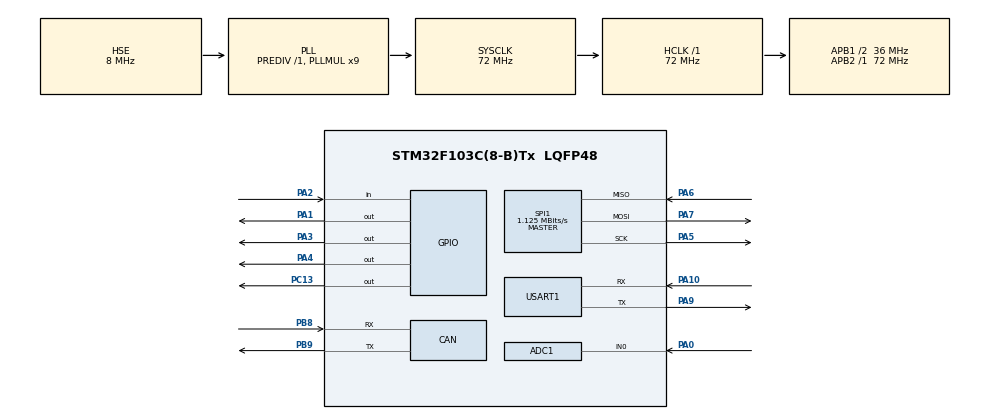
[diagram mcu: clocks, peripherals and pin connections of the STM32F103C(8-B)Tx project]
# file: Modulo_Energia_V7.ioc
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ADC1.Channel-0\#ChannelRegularConversion=ADC_CHANNEL_0
ADC1.ContinuousConvMode=ENABLE
ADC1.NbrOfConversion=1
ADC1.NbrOfConversionFlag=1
ADC1.Rank-0\#ChannelRegularConversion=1
ADC1.SamplingTime-0\#ChannelRegularConversion=ADC_SAMPLETIME_1CYCLE_5
ADC1.master=1
CAN.CalculateTimeBit=1333
CAN.CalculateTimeQuantum=444.44444444444446
Mcu.Family=STM32F1
Mcu.Name=STM32F103C(8-B)Tx
Mcu.Package=LQFP48
NVIC.PriorityGroup=NVIC_PRIORITYGROUP_4
NVIC.TIM2_IRQn=true\:0\:0\:false\:false\:true\:true\:true
NVIC.USB_LP_CAN1_RX0_IRQn=true\:0\:0\:false\:false\:true\:true\:true
PA0-WKUP.Signal=ADCx_IN0
PA1.Signal=GPIO_Output
PA10.Mode=Asynchronous
PA10.Signal=USART1_RX
PA2.Signal=GPIO_Input
PA3.Signal=GPIO_Output
PA4.Signal=GPIO_Output
PA5.Mode=Full_Duplex_Master
PA5.Signal=SPI1_SCK
PA6.Mode=Full_Duplex_Master
PA6.Signal=SPI1_MISO
PA7.Mode=Full_Duplex_Master
PA7.Signal=SPI1_MOSI
PA9.Mode=Asynchronous
PA9.Signal=USART1_TX
PB8.Mode=Master
PB8.Signal=CAN_RX
PB9.Mode=Master
PB9.Signal=CAN_TX
PC13-TAMPER-RTC.Signal=GPIO_Output
PD0-OSC_IN.Mode=HSE-External-Oscillator
PD0-OSC_IN.Signal=RCC_OSC_IN
PD1-OSC_OUT.Mode=HSE-External-Oscillator
PD1-OSC_OUT.Signal=RCC_OSC_OUT
ProjectManager.HeapSize=0x200
ProjectManager.StackSize=0x400
ProjectManager.TargetToolchain=TrueSTUDIO
RCC.ADCPresc=RCC_ADCPCLK2_DIV6
RCC.AHBFreq_Value=72000000
RCC.APB1CLKDivider=RCC_HCLK_DIV2
RCC.APB1Freq_Value=36000000
RCC.APB1TimFreq_Value=72000000
RCC.APB2Freq_Value=72000000
RCC.APB2TimFreq_Value=72000000
RCC.HCLKFreq_Value=72000000
RCC.PLLMUL=RCC_PLL_MUL9
RCC.PLLSourceVirtual=RCC_PLLSOURCE_HSE
RCC.SYSCLKFreq_VALUE=72000000
RCC.SYSCLKSource=RCC_SYSCLKSOURCE_PLLCLK
RCC.USBFreq_Value=72000000
SH.ADCx_IN0.0=ADC1_IN0,IN0
SPI1.BaudRatePrescaler=SPI_BAUDRATEPRESCALER_64
SPI1.CalculateBaudRate=1.125 MBits/s
SPI1.Direction=SPI_DIRECTION_2LINES
SPI1.Mode=SPI_MODE_MASTER
SPI1.VirtualType=VM_MASTER
TIM2.Period=999
TIM2.Prescaler=7999
USART1.VirtualMode=VM_ASYNC
VP_SYS_VS_ND.Mode=No_Debug
VP_TIM2_VS_ClockSourceINT.Mode=Internal
board=custom

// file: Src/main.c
/*

	 .d88888b.  8888888b.  8888888888 888b     d888 888     888  .d8888b.
	d88P" "Y88b 888   Y88b 888        8888b   d8888 888     888 d88P  Y88b
	888     888 888    888 888        88888b.d88888 888     888 Y88b.
	888     888 888   d88P 8888888    888Y88888P888 888     888  "Y888b.
	888     888 8888888P"  888        888 Y888P 888 888     888     "Y88b.
	888     888 888 T88b   888        888  Y8P  888 888     888       "888
	Y88b. .d88P 888  T88b  888        888   "   888 Y88b. .d88P Y88b  d88P
	 "Y88888P"  888   T88b 8888888888 888       888  "Y88888P"   "Y8888P"

  ******************************************************************************
  *        M  O  D  U  L  O     E  N  E  R  G  I  A - Versão 13 - 21/03/2020
  ******************************************************************************

	CAN GPIO Configuration
    PB8  -> CAN_RX
    PB9  -> CAN_TX

    PB7  -> LED Azul

    PA2  ->  Chave magnétca (Sensor)
    PA1  ->  Comando para o Relé

    PA0  ->  ADC corrente

	PA3  -> CS
	PA4  -> CE
	PA5  -> SCK
	PA6  -> MISO
	PA7  -> MOSI

   __________________________
  |                          |
  |        Tabela IDs        |
  |__________________________|
  | Desligar:          0x001 |
  | Comando:           0x003 |
  | Pergunta Dados:    0x005 |
  |                          |
  | Resposta Motor:    0x004 |
  |	Resposta Energia:  0x006 |
  | Resposta Sensores: 0x008 |
  |__________________________|

*/

/**
  ******************************************************************************
  * @file           : main.c
  * @brief          : Main program body
  ******************************************************************************
  * @attention
  *
  * <h2><center>&copy; Copyright (c) 2020 STMicroelectronics.
  * All rights reserved.</center></h2>
  *
  * This software component is licensed by ST under BSD 3-Clause license,
  * the "License"; You may not use this file except in compliance with the
  * License. You may obtain a copy of the License at:
  *                        opensource.org/licenses/BSD-3-Clause
  *
  ******************************************************************************
  */
/* USER CODE END Header */

#include "main.h"

/* USER CODE BEGIN Includes */
#include "MY_NRF24.h"
/* USER CODE END Includes */

ADC_HandleTypeDef hadc1;
CAN_HandleTypeDef hcan;
SPI_HandleTypeDef hspi1;
TIM_HandleTypeDef htim2;
UART_HandleTypeDef huart1;

static CAN_TxHeaderTypeDef TxHeader;
static CAN_RxHeaderTypeDef RxHeader;
uint8_t TxData[8];
uint8_t RxData[8];
uint32_t TxMailbox;
uint32_t corrente;

union U{
		uint32_t var32;
		uint8_t var8[4];
	}u;

void SystemClock_Config(void);
static void MX_GPIO_Init(void);
static void MX_TIM2_Init(void);
static void MX_SPI1_Init(void);
static void MX_CAN_Init(void);
static void MX_ADC1_Init(void);
static void MX_USART1_UART_Init(void);

/* USER CODE BEGIN 0 */
int  cont=0; // variavel para comando de desligar

//-----nRF2401------
	uint64_t RxpipeAddrs = 0xe7e7e7e7e7;
	uint8_t myRxData[8];
	uint8_t myAckPayload[8];
/* USER CODE END 0 */

int main(void)
{

  /* MCU Configuration--------------------------------------------------------*/

  /* Reset of all peripherals, Initializes the Flash interface and the Systick. */
  HAL_Init();

  /* Configure the system clock */
  SystemClock_Config();

  /* Initialize all configured peripherals */
  MX_GPIO_Init();
  MX_TIM2_Init();
  MX_SPI1_Init();
  MX_CAN_Init();
  MX_ADC1_Init();
  MX_USART1_UART_Init();

  HAL_TIM_Base_Start_IT(&htim2);
  HAL_ADC_Start (&hadc1);

  /* USER CODE BEGIN 2 */
  NRF24_begin(GPIOA,GPIO_PIN_3,GPIO_PIN_4, hspi1); //CS CE

  //*** TRANSMIT - ACK ***//
  NRF24_setAutoAck(true);
  NRF24_setChannel(103);
  NRF24_setPayloadSize(32);
  NRF24_openReadingPipe(1,RxpipeAddrs);

  NRF24_enableDynamicPayloads();
  NRF24_enableAckPayload();

  NRF24_startListening();

  /* USER CODE END 2 */

  HAL_GPIO_WritePin(GPIOA, GPIO_PIN_1, GPIO_PIN_RESET); //liga a energia

  HAL_GPIO_WritePin(GPIOB, GPIO_PIN_11, GPIO_PIN_SET);
  HAL_Delay(250);
  HAL_GPIO_WritePin(GPIOB, GPIO_PIN_11, GPIO_PIN_RESET);
  HAL_Delay(100);
  HAL_GPIO_WritePin(GPIOB, GPIO_PIN_11, GPIO_PIN_SET);
  HAL_Delay(250);
  HAL_GPIO_WritePin(GPIOB, GPIO_PIN_11, GPIO_PIN_RESET);
  HAL_Delay(100);
  HAL_GPIO_WritePin(GPIOB, GPIO_PIN_11, GPIO_PIN_SET);
  HAL_Delay(250);
  HAL_GPIO_WritePin(GPIOB, GPIO_PIN_11, GPIO_PIN_RESET);

  /* Infinite loop */
  /* USER CODE BEGIN WHILE */
  while (1)
  {

	HAL_ADC_PollForConversion (&hadc1, 1000);
	corrente = HAL_ADC_GetValue (&hadc1);
	u.var32 = corrente/23;

	myAckPayload[0] = u.var8[0];
	myAckPayload[1] = u.var8[1];
	myAckPayload[2] = u.var8[2];
	myAckPayload[3] = u.var8[3];
	myAckPayload[4] = 0;
	myAckPayload[5] = 0;
	myAckPayload[6] = 0;
	myAckPayload[7] = 0;

	if (NRF24_available()){
		NRF24_read(myRxData, 8);
		NRF24_writeAckPayload(1, myAckPayload, 8);

		HAL_GPIO_TogglePin(GPIOC,GPIO_PIN_13);
	}

	TxHeader.StdId = 0x003; // responde com id 0x00B
	TxData[0] = myRxData[0];
	TxData[1] = myRxData[1];
	TxData[2] = myRxData[2];
	TxData[3] = myRxData[3];
	TxData[4] = myRxData[4];
	TxData[5] = myRxData[5];
	TxData[6] = myRxData[6];
	TxData[7] = myRxData[7];

	if (HAL_CAN_AddTxMessage(&hcan, &TxHeader, TxData, &TxMailbox) != HAL_OK){
		Error_Handler();
	}

	HAL_GPIO_TogglePin(GPIOB,GPIO_PIN_7);

	HAL_Delay(1000);

  }

}

void SystemClock_Config(void)
{
  RCC_OscInitTypeDef RCC_OscInitStruct = {0};
  RCC_ClkInitTypeDef RCC_ClkInitStruct = {0};
  RCC_PeriphCLKInitTypeDef PeriphClkInit = {0};

  /** Initializes the CPU, AHB and APB busses clocks
  */
  RCC_OscInitStruct.OscillatorType = RCC_OSCILLATORTYPE_HSE;
  RCC_OscInitStruct.HSEState = RCC_HSE_ON;
  RCC_OscInitStruct.HSEPredivValue = RCC_HSE_PREDIV_DIV1;
  RCC_OscInitStruct.HSIState = RCC_HSI_ON;
  RCC_OscInitStruct.PLL.PLLState = RCC_PLL_ON;
  RCC_OscInitStruct.PLL.PLLSource = RCC_PLLSOURCE_HSE;
  RCC_OscInitStruct.PLL.PLLMUL = RCC_PLL_MUL9;
  if (HAL_RCC_OscConfig(&RCC_OscInitStruct) != HAL_OK)
  {
    Error_Handler();
  }
  /** Initializes the CPU, AHB and APB busses clocks
  */
  RCC_ClkInitStruct.ClockType = RCC_CLOCKTYPE_HCLK|RCC_CLOCKTYPE_SYSCLK
                              |RCC_CLOCKTYPE_PCLK1|RCC_CLOCKTYPE_PCLK2;
  RCC_ClkInitStruct.SYSCLKSource = RCC_SYSCLKSOURCE_PLLCLK;
  RCC_ClkInitStruct.AHBCLKDivider = RCC_SYSCLK_DIV1;
  RCC_ClkInitStruct.APB1CLKDivider = RCC_HCLK_DIV2;
  RCC_ClkInitStruct.APB2CLKDivider = RCC_HCLK_DIV1;

  if (HAL_RCC_ClockConfig(&RCC_ClkInitStruct, FLASH_LATENCY_2) != HAL_OK)
  {
    Error_Handler();
  }
  PeriphClkInit.PeriphClockSelection = RCC_PERIPHCLK_ADC;
  PeriphClkInit.AdcClockSelection = RCC_ADCPCLK2_DIV6;
  if (HAL_RCCEx_PeriphCLKConfig(&PeriphClkInit) != HAL_OK)
  {
    Error_Handler();
  }
}

static void MX_ADC1_Init(void)
{

  ADC_ChannelConfTypeDef sConfig = {0};

  /** Common config
  */
  hadc1.Instance = ADC1;
  hadc1.Init.ScanConvMode = ADC_SCAN_DISABLE;
  hadc1.Init.ContinuousConvMode = ENABLE;
  hadc1.Init.DiscontinuousConvMode = DISABLE;
  hadc1.Init.ExternalTrigConv = ADC_SOFTWARE_START;
  hadc1.Init.DataAlign = ADC_DATAALIGN_RIGHT;
  hadc1.Init.NbrOfConversion = 1;
  if (HAL_ADC_Init(&hadc1) != HAL_OK)
  {
    Error_Handler();
  }
  /** Configure Regular Channel
  */
  sConfig.Channel = ADC_CHANNEL_0;
  sConfig.Rank = ADC_REGULAR_RANK_1;
  sConfig.SamplingTime = ADC_SAMPLETIME_1CYCLE_5;
  if (HAL_ADC_ConfigChannel(&hadc1, &sConfig) != HAL_OK)
  {
    Error_Handler();
  }

}

static void MX_CAN_Init(void)
{

  hcan.Instance = CAN1;
  hcan.Init.Prescaler = 9;
  hcan.Init.Mode = CAN_MODE_NORMAL;
  hcan.Init.SyncJumpWidth = CAN_SJW_1TQ;
  hcan.Init.TimeSeg1 = CAN_BS1_13TQ;
  hcan.Init.TimeSeg2 = CAN_BS2_2TQ;
  hcan.Init.TimeTriggeredMode = DISABLE;
  hcan.Init.AutoBusOff = DISABLE;
  hcan.Init.AutoWakeUp = DISABLE;
  hcan.Init.AutoRetransmission = DISABLE;
  hcan.Init.ReceiveFifoLocked = DISABLE;
  hcan.Init.TransmitFifoPriority = DISABLE;
  if (HAL_CAN_Init(&hcan) != HAL_OK)
  {
    Error_Handler();
  }
  /* USER CODE BEGIN CAN_Init 2 */
  if (HAL_CAN_ActivateNotification(&hcan, CAN_IT_RX_FIFO0_MSG_PENDING) != HAL_OK)
  {
	Error_Handler();
  }

  /* Configure the CAN Filter */
  CAN_FilterTypeDef  sFilterConfig;
  sFilterConfig.FilterBank = 0;
  sFilterConfig.FilterMode = CAN_FILTERMODE_IDMASK;
  sFilterConfig.FilterScale = CAN_FILTERSCALE_32BIT;
  sFilterConfig.FilterIdHigh     = 0x000<<5; //0x000
  sFilterConfig.FilterIdLow      = 0x0000;
  sFilterConfig.FilterMaskIdHigh = 0x700<<5; // mascara que filtra
  sFilterConfig.FilterMaskIdLow  = 0x0000;
  sFilterConfig.FilterFIFOAssignment = CAN_RX_FIFO0;
  sFilterConfig.FilterActivation = ENABLE;
  sFilterConfig.SlaveStartFilterBank = 14;
  if (HAL_CAN_ConfigFilter(&hcan, &sFilterConfig) != HAL_OK)
  {
    /* Filter configuration Error */
    Error_Handler();
  }

  /* Configure Transmission process */
  TxHeader.StdId = 0x001;
  TxHeader.ExtId = 0x001;
  TxHeader.RTR = CAN_RTR_DATA;
  TxHeader.IDE = CAN_ID_STD;
  TxHeader.DLC = 8;
  TxHeader.TransmitGlobalTime = DISABLE;

  /* Start the CAN peripheral */
  if (HAL_CAN_Start(&hcan) != HAL_OK)
  {
    /* Start Error */
    Error_Handler();
  }

  /* USER CODE END CAN_Init 2 */

}

static void MX_SPI1_Init(void)
{

  /* SPI1 parameter configuration*/
  hspi1.Instance = SPI1;
  hspi1.Init.Mode = SPI_MODE_MASTER;
  hspi1.Init.Direction = SPI_DIRECTION_2LINES;
  hspi1.Init.DataSize = SPI_DATASIZE_8BIT;
  hspi1.Init.CLKPolarity = SPI_POLARITY_LOW;
  hspi1.Init.CLKPhase = SPI_PHASE_1EDGE;
  hspi1.Init.NSS = SPI_NSS_SOFT;
  hspi1.Init.BaudRatePrescaler = SPI_BAUDRATEPRESCALER_64;
  hspi1.Init.FirstBit = SPI_FIRSTBIT_MSB;
  hspi1.Init.TIMode = SPI_TIMODE_DISABLE;
  hspi1.Init.CRCCalculation = SPI_CRCCALCULATION_DISABLE;
  hspi1.Init.CRCPolynomial = 10;
  if (HAL_SPI_Init(&hspi1) != HAL_OK)
  {
    Error_Handler();
  }

}

static void MX_TIM2_Init(void)
{

  TIM_ClockConfigTypeDef sClockSourceConfig = {0};
  TIM_MasterConfigTypeDef sMasterConfig = {0};

  htim2.Instance = TIM2;
  htim2.Init.Prescaler = 35999;
  htim2.Init.CounterMode = TIM_COUNTERMODE_UP;
  htim2.Init.Period = 999;
  htim2.Init.ClockDivision = TIM_CLOCKDIVISION_DIV1;
  htim2.Init.AutoReloadPreload = TIM_AUTORELOAD_PRELOAD_DISABLE;
  if (HAL_TIM_Base_Init(&htim2) != HAL_OK)
  {
    Error_Handler();
  }
  sClockSourceConfig.ClockSource = TIM_CLOCKSOURCE_INTERNAL;
  if (HAL_TIM_ConfigClockSource(&htim2, &sClockSourceConfig) != HAL_OK)
  {
    Error_Handler();
  }
  sMasterConfig.MasterOutputTrigger = TIM_TRGO_RESET;
  sMasterConfig.MasterSlaveMode = TIM_MASTERSLAVEMODE_DISABLE;
  if (HAL_TIMEx_MasterConfigSynchronization(&htim2, &sMasterConfig) != HAL_OK)
  {
    Error_Handler();
  }

}

static void MX_USART1_UART_Init(void)
{

  huart1.Instance = USART1;
  huart1.Init.BaudRate = 115200;
  huart1.Init.WordLength = UART_WORDLENGTH_8B;
  huart1.Init.StopBits = UART_STOPBITS_1;
  huart1.Init.Parity = UART_PARITY_NONE;
  huart1.Init.Mode = UART_MODE_TX_RX;
  huart1.Init.HwFlowCtl = UART_HWCONTROL_NONE;
  huart1.Init.OverSampling = UART_OVERSAMPLING_16;
  if (HAL_UART_Init(&huart1) != HAL_OK)
  {
    Error_Handler();
  }

}

static void MX_GPIO_Init(void)
{
  GPIO_InitTypeDef GPIO_InitStruct = {0};

  /* GPIO Ports Clock Enable */
  __HAL_RCC_GPIOC_CLK_ENABLE();
  __HAL_RCC_GPIOD_CLK_ENABLE();
  __HAL_RCC_GPIOA_CLK_ENABLE();
  __HAL_RCC_GPIOB_CLK_ENABLE();

  /*Configure GPIO pin Output Level */
  HAL_GPIO_WritePin(GPIOC, GPIO_PIN_13, GPIO_PIN_RESET);
  HAL_GPIO_WritePin(GPIOB, GPIO_PIN_11, GPIO_PIN_RESET);
  /*Configure GPIO pin Output Level */
  HAL_GPIO_WritePin(GPIOA,GPIO_PIN_3|GPIO_PIN_4, GPIO_PIN_RESET);
  HAL_GPIO_WritePin(GPIOA, GPIO_PIN_1, GPIO_PIN_SET);

  /*Configure GPIO pin : PC13 */
  GPIO_InitStruct.Pin = GPIO_PIN_13;
  GPIO_InitStruct.Mode = GPIO_MODE_OUTPUT_PP;
  GPIO_InitStruct.Pull = GPIO_NOPULL;
  GPIO_InitStruct.Speed = GPIO_SPEED_FREQ_LOW;
  HAL_GPIO_Init(GPIOC, &GPIO_InitStruct);

  /*Configure GPIO pins : PA1 PA3 PA4 */
  GPIO_InitStruct.Pin = GPIO_PIN_1|GPIO_PIN_3|GPIO_PIN_4;
  GPIO_InitStruct.Mode = GPIO_MODE_OUTPUT_PP;
  GPIO_InitStruct.Pull = GPIO_NOPULL;
  GPIO_InitStruct.Speed = GPIO_SPEED_FREQ_LOW;
  HAL_GPIO_Init(GPIOA, &GPIO_InitStruct);

  /*Configure GPIO pin : PA2 */
  GPIO_InitStruct.Pin = GPIO_PIN_2;
  GPIO_InitStruct.Mode = GPIO_MODE_INPUT;
  GPIO_InitStruct.Pull = GPIO_NOPULL;
  HAL_GPIO_Init(GPIOA, &GPIO_InitStruct);

  /*Configure GPIO pin : PB7 */
  GPIO_InitStruct.Pin = GPIO_PIN_7;
  GPIO_InitStruct.Mode = GPIO_MODE_OUTPUT_PP;
  GPIO_InitStruct.Pull = GPIO_NOPULL;
  GPIO_InitStruct.Speed = GPIO_SPEED_FREQ_LOW;
  HAL_GPIO_Init(GPIOB, &GPIO_InitStruct);

  GPIO_InitStruct.Pin = GPIO_PIN_11;
  GPIO_InitStruct.Mode = GPIO_MODE_OUTPUT_PP;
  GPIO_InitStruct.Pull = GPIO_NOPULL;
  GPIO_InitStruct.Speed = GPIO_SPEED_FREQ_LOW;
  HAL_GPIO_Init(GPIOB, &GPIO_InitStruct);

}

/* USER CODE BEGIN 4 */
void HAL_TIM_PeriodElapsedCallback(TIM_HandleTypeDef*htim)
{
    if (htim->Instance==TIM2){

        if (HAL_GPIO_ReadPin(GPIOA,GPIO_PIN_2)){
          cont++;
    	  HAL_GPIO_TogglePin(GPIOC, GPIO_PIN_13);

	    	if(cont>= 4){
	    	  cont=0;
		      HAL_GPIO_WritePin(GPIOB, GPIO_PIN_11, GPIO_PIN_SET);
		      HAL_GPIO_WritePin(GPIOA, GPIO_PIN_1, GPIO_PIN_SET);
	    	}
    	}

    	else {
			  HAL_GPIO_WritePin(GPIOB, GPIO_PIN_11, GPIO_PIN_RESET);
    	  cont=0;
    	}
    }
}

void HAL_CAN_RxFifo0MsgPendingCallback(CAN_HandleTypeDef *hcan)
{
  //HAL_GPIO_TogglePin(GPIOC,GPIO_PIN_13);
  /* Get RX message */
  if (HAL_CAN_GetRxMessage(hcan, CAN_RX_FIFO0, &RxHeader, RxData) != HAL_OK)
  {

    Error_Handler();
  }
}
/* USER CODE END 4 */

void Error_Handler(void)
{
}

/************************ (C) COPYRIGHT STMicroelectronics *****END OF FILE****/
